VERSION 5.7 ;
  NOWIREEXTENSIONATPIN ON ;
  DIVIDERCHAR "/" ;
  BUSBITCHARS "[]" ;
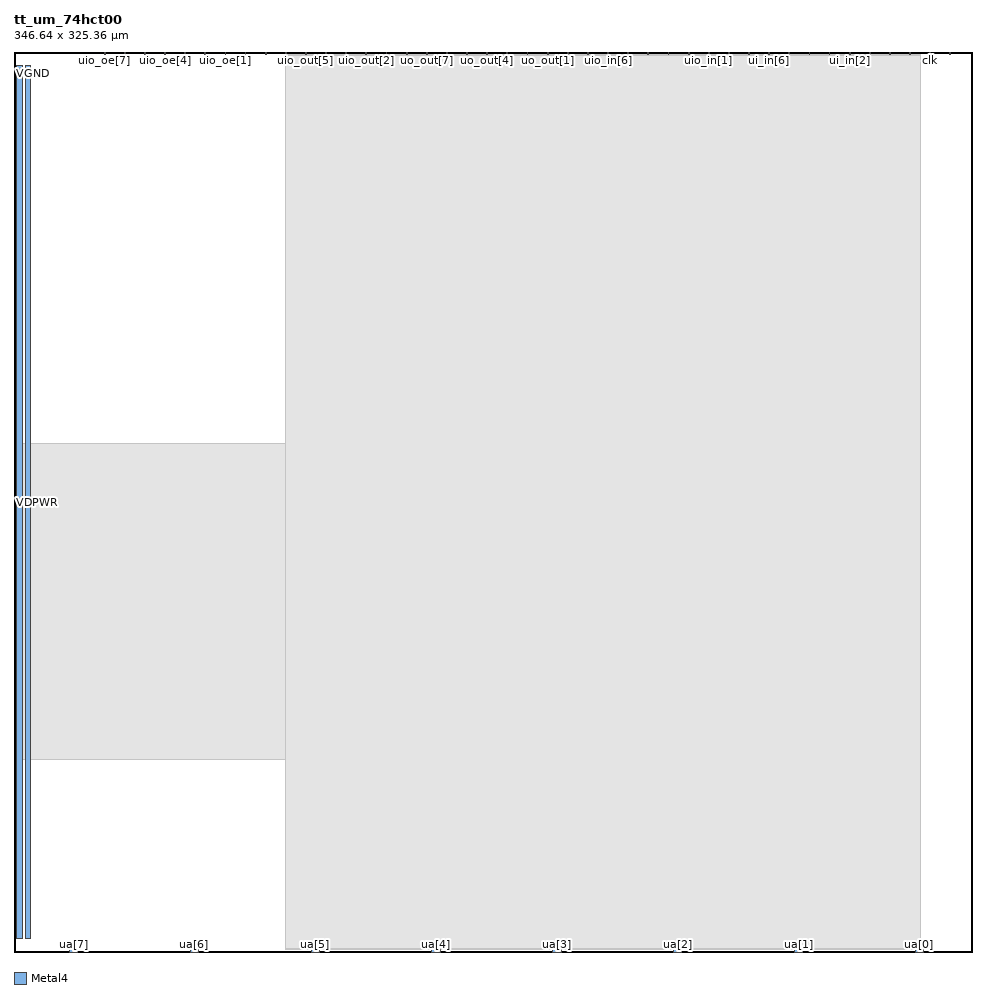
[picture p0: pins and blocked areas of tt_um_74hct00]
MACRO tt_um_74hct00
  CLASS BLOCK ;
  FOREIGN tt_um_74hct00 ;
  ORIGIN 0.000 0.000 ;
  SIZE 346.640 BY 325.360 ;
  PIN clk
    PORT
      LAYER Metal4 ;
        RECT 331.090 324.360 331.390 325.360 ;
    END
  END clk
  PIN ena
    PORT
      LAYER Metal4 ;
        RECT 338.370 324.360 338.670 325.360 ;
    END
  END ena
  PIN rst_n
    PORT
      LAYER Metal4 ;
        RECT 323.810 324.360 324.110 325.360 ;
    END
  END rst_n
  PIN ua[0]
    ANTENNADIFFAREA 39.000000 ;
    PORT
      LAYER Metal4 ;
        RECT 325.820 0.000 328.820 1.000 ;
    END
  END ua[0]
  PIN ua[1]
    ANTENNADIFFAREA 39.000000 ;
    PORT
      LAYER Metal4 ;
        RECT 282.140 0.000 285.140 1.000 ;
    END
  END ua[1]
  PIN ua[2]
    ANTENNADIFFAREA 39.000000 ;
    PORT
      LAYER Metal4 ;
        RECT 238.460 0.000 241.460 1.000 ;
    END
  END ua[2]
  PIN ua[3]
    ANTENNADIFFAREA 39.000000 ;
    PORT
      LAYER Metal4 ;
        RECT 194.780 0.000 197.780 1.000 ;
    END
  END ua[3]
  PIN ua[4]
    ANTENNAGATEAREA 3.000000 ;
    PORT
      LAYER Metal4 ;
        RECT 151.100 0.000 154.100 1.000 ;
    END
  END ua[4]
  PIN ua[5]
    PORT
      LAYER Metal4 ;
        RECT 107.420 0.000 110.420 1.000 ;
    END
  END ua[5]
  PIN ua[6]
    PORT
      LAYER Metal4 ;
        RECT 63.740 0.000 66.740 1.000 ;
    END
  END ua[6]
  PIN ua[7]
    PORT
      LAYER Metal4 ;
        RECT 20.060 0.000 23.060 1.000 ;
    END
  END ua[7]
  PIN ui_in[0]
    ANTENNAGATEAREA 3.000000 ;
    PORT
      LAYER Metal4 ;
        RECT 316.530 324.360 316.830 325.360 ;
    END
  END ui_in[0]
  PIN ui_in[1]
    ANTENNAGATEAREA 3.000000 ;
    PORT
      LAYER Metal4 ;
        RECT 309.250 324.360 309.550 325.360 ;
    END
  END ui_in[1]
  PIN ui_in[2]
    ANTENNAGATEAREA 3.000000 ;
    PORT
      LAYER Metal4 ;
        RECT 301.970 324.360 302.270 325.360 ;
    END
  END ui_in[2]
  PIN ui_in[3]
    ANTENNAGATEAREA 3.000000 ;
    PORT
      LAYER Metal4 ;
        RECT 294.690 324.360 294.990 325.360 ;
    END
  END ui_in[3]
  PIN ui_in[4]
    ANTENNAGATEAREA 3.000000 ;
    PORT
      LAYER Metal4 ;
        RECT 287.410 324.360 287.710 325.360 ;
    END
  END ui_in[4]
  PIN ui_in[5]
    ANTENNAGATEAREA 3.000000 ;
    PORT
      LAYER Metal4 ;
        RECT 280.130 324.360 280.430 325.360 ;
    END
  END ui_in[5]
  PIN ui_in[6]
    ANTENNAGATEAREA 3.000000 ;
    PORT
      LAYER Metal4 ;
        RECT 272.850 324.360 273.150 325.360 ;
    END
  END ui_in[6]
  PIN ui_in[7]
    ANTENNAGATEAREA 3.000000 ;
    PORT
      LAYER Metal4 ;
        RECT 265.570 324.360 265.870 325.360 ;
    END
  END ui_in[7]
  PIN uio_in[0]
    PORT
      LAYER Metal4 ;
        RECT 258.290 324.360 258.590 325.360 ;
    END
  END uio_in[0]
  PIN uio_in[1]
    PORT
      LAYER Metal4 ;
        RECT 251.010 324.360 251.310 325.360 ;
    END
  END uio_in[1]
  PIN uio_in[2]
    PORT
      LAYER Metal4 ;
        RECT 243.730 324.360 244.030 325.360 ;
    END
  END uio_in[2]
  PIN uio_in[3]
    PORT
      LAYER Metal4 ;
        RECT 236.450 324.360 236.750 325.360 ;
    END
  END uio_in[3]
  PIN uio_in[4]
    PORT
      LAYER Metal4 ;
        RECT 229.170 324.360 229.470 325.360 ;
    END
  END uio_in[4]
  PIN uio_in[5]
    PORT
      LAYER Metal4 ;
        RECT 221.890 324.360 222.190 325.360 ;
    END
  END uio_in[5]
  PIN uio_in[6]
    PORT
      LAYER Metal4 ;
        RECT 214.610 324.360 214.910 325.360 ;
    END
  END uio_in[6]
  PIN uio_in[7]
    PORT
      LAYER Metal4 ;
        RECT 207.330 324.360 207.630 325.360 ;
    END
  END uio_in[7]
  PIN uio_oe[0]
    PORT
      LAYER Metal4 ;
        RECT 83.570 324.360 83.870 325.360 ;
    END
  END uio_oe[0]
  PIN uio_oe[1]
    PORT
      LAYER Metal4 ;
        RECT 76.290 324.360 76.590 325.360 ;
    END
  END uio_oe[1]
  PIN uio_oe[2]
    PORT
      LAYER Metal4 ;
        RECT 69.010 324.360 69.310 325.360 ;
    END
  END uio_oe[2]
  PIN uio_oe[3]
    PORT
      LAYER Metal4 ;
        RECT 61.730 324.360 62.030 325.360 ;
    END
  END uio_oe[3]
  PIN uio_oe[4]
    PORT
      LAYER Metal4 ;
        RECT 54.450 324.360 54.750 325.360 ;
    END
  END uio_oe[4]
  PIN uio_oe[5]
    PORT
      LAYER Metal4 ;
        RECT 47.170 324.360 47.470 325.360 ;
    END
  END uio_oe[5]
  PIN uio_oe[6]
    PORT
      LAYER Metal4 ;
        RECT 39.890 324.360 40.190 325.360 ;
    END
  END uio_oe[6]
  PIN uio_oe[7]
    PORT
      LAYER Metal4 ;
        RECT 32.610 324.360 32.910 325.360 ;
    END
  END uio_oe[7]
  PIN uio_out[0]
    PORT
      LAYER Metal4 ;
        RECT 141.810 324.360 142.110 325.360 ;
    END
  END uio_out[0]
  PIN uio_out[1]
    PORT
      LAYER Metal4 ;
        RECT 134.530 324.360 134.830 325.360 ;
    END
  END uio_out[1]
  PIN uio_out[2]
    PORT
      LAYER Metal4 ;
        RECT 127.250 324.360 127.550 325.360 ;
    END
  END uio_out[2]
  PIN uio_out[3]
    PORT
      LAYER Metal4 ;
        RECT 119.970 324.360 120.270 325.360 ;
    END
  END uio_out[3]
  PIN uio_out[4]
    PORT
      LAYER Metal4 ;
        RECT 112.690 324.360 112.990 325.360 ;
    END
  END uio_out[4]
  PIN uio_out[5]
    PORT
      LAYER Metal4 ;
        RECT 105.410 324.360 105.710 325.360 ;
    END
  END uio_out[5]
  PIN uio_out[6]
    PORT
      LAYER Metal4 ;
        RECT 98.130 324.360 98.430 325.360 ;
    END
  END uio_out[6]
  PIN uio_out[7]
    PORT
      LAYER Metal4 ;
        RECT 90.850 324.360 91.150 325.360 ;
    END
  END uio_out[7]
  PIN uo_out[0]
    PORT
      LAYER Metal4 ;
        RECT 200.050 324.360 200.350 325.360 ;
    END
  END uo_out[0]
  PIN uo_out[1]
    PORT
      LAYER Metal4 ;
        RECT 192.770 324.360 193.070 325.360 ;
    END
  END uo_out[1]
  PIN uo_out[2]
    PORT
      LAYER Metal4 ;
        RECT 185.490 324.360 185.790 325.360 ;
    END
  END uo_out[2]
  PIN uo_out[3]
    PORT
      LAYER Metal4 ;
        RECT 178.210 324.360 178.510 325.360 ;
    END
  END uo_out[3]
  PIN uo_out[4]
    PORT
      LAYER Metal4 ;
        RECT 170.930 324.360 171.230 325.360 ;
    END
  END uo_out[4]
  PIN uo_out[5]
    PORT
      LAYER Metal4 ;
        RECT 163.650 324.360 163.950 325.360 ;
    END
  END uo_out[5]
  PIN uo_out[6]
    PORT
      LAYER Metal4 ;
        RECT 156.370 324.360 156.670 325.360 ;
    END
  END uo_out[6]
  PIN uo_out[7]
    PORT
      LAYER Metal4 ;
        RECT 149.090 324.360 149.390 325.360 ;
    END
  END uo_out[7]
  PIN VDPWR
    DIRECTION INOUT ;
    USE POWER ;
    ANTENNAGATEAREA 388.799988 ;
    ANTENNADIFFAREA 420.839996 ;
    PORT
      LAYER Metal4 ;
        RECT 1.000 5.000 3.000 320.360 ;
    END
  END VDPWR
  PIN VGND
    DIRECTION INOUT ;
    USE GROUND ;
    ANTENNAGATEAREA 388.799988 ;
    ANTENNADIFFAREA 420.839996 ;
    PORT
      LAYER Metal4 ;
        RECT 4.000 5.000 6.000 320.360 ;
    END
  END VGND
  OBS
      LAYER Nwell ;
        RECT 114.850 105.310 207.640 149.690 ;
      LAYER Metal1 ;
        RECT 106.820 91.000 216.005 183.895 ;
      LAYER Metal2 ;
        RECT 107.070 91.040 216.005 183.895 ;
      LAYER Metal3 ;
        RECT 1.030 69.500 327.770 183.915 ;
      LAYER Metal4 ;
        RECT 98.730 324.060 105.110 324.360 ;
        RECT 106.010 324.060 112.390 324.360 ;
        RECT 113.290 324.060 119.670 324.360 ;
        RECT 120.570 324.060 126.950 324.360 ;
        RECT 127.850 324.060 134.230 324.360 ;
        RECT 135.130 324.060 141.510 324.360 ;
        RECT 142.410 324.060 148.790 324.360 ;
        RECT 149.690 324.060 156.070 324.360 ;
        RECT 156.970 324.060 163.350 324.360 ;
        RECT 164.250 324.060 170.630 324.360 ;
        RECT 171.530 324.060 177.910 324.360 ;
        RECT 178.810 324.060 185.190 324.360 ;
        RECT 186.090 324.060 192.470 324.360 ;
        RECT 193.370 324.060 199.750 324.360 ;
        RECT 200.650 324.060 207.030 324.360 ;
        RECT 207.930 324.060 214.310 324.360 ;
        RECT 215.210 324.060 221.590 324.360 ;
        RECT 222.490 324.060 228.870 324.360 ;
        RECT 229.770 324.060 236.150 324.360 ;
        RECT 237.050 324.060 243.430 324.360 ;
        RECT 244.330 324.060 250.710 324.360 ;
        RECT 251.610 324.060 257.990 324.360 ;
        RECT 258.890 324.060 265.270 324.360 ;
        RECT 266.170 324.060 272.550 324.360 ;
        RECT 273.450 324.060 279.830 324.360 ;
        RECT 280.730 324.060 287.110 324.360 ;
        RECT 288.010 324.060 294.390 324.360 ;
        RECT 295.290 324.060 301.670 324.360 ;
        RECT 302.570 324.060 308.950 324.360 ;
        RECT 309.850 324.060 316.230 324.360 ;
        RECT 317.130 324.060 323.510 324.360 ;
        RECT 324.410 324.060 327.820 324.360 ;
        RECT 98.000 1.300 327.820 324.060 ;
        RECT 98.000 1.000 107.120 1.300 ;
        RECT 110.720 1.000 150.800 1.300 ;
        RECT 154.400 1.000 194.480 1.300 ;
        RECT 198.080 1.000 238.160 1.300 ;
        RECT 241.760 1.000 281.840 1.300 ;
        RECT 285.440 1.000 325.520 1.300 ;
  END
END tt_um_74hct00
END LIBRARY

